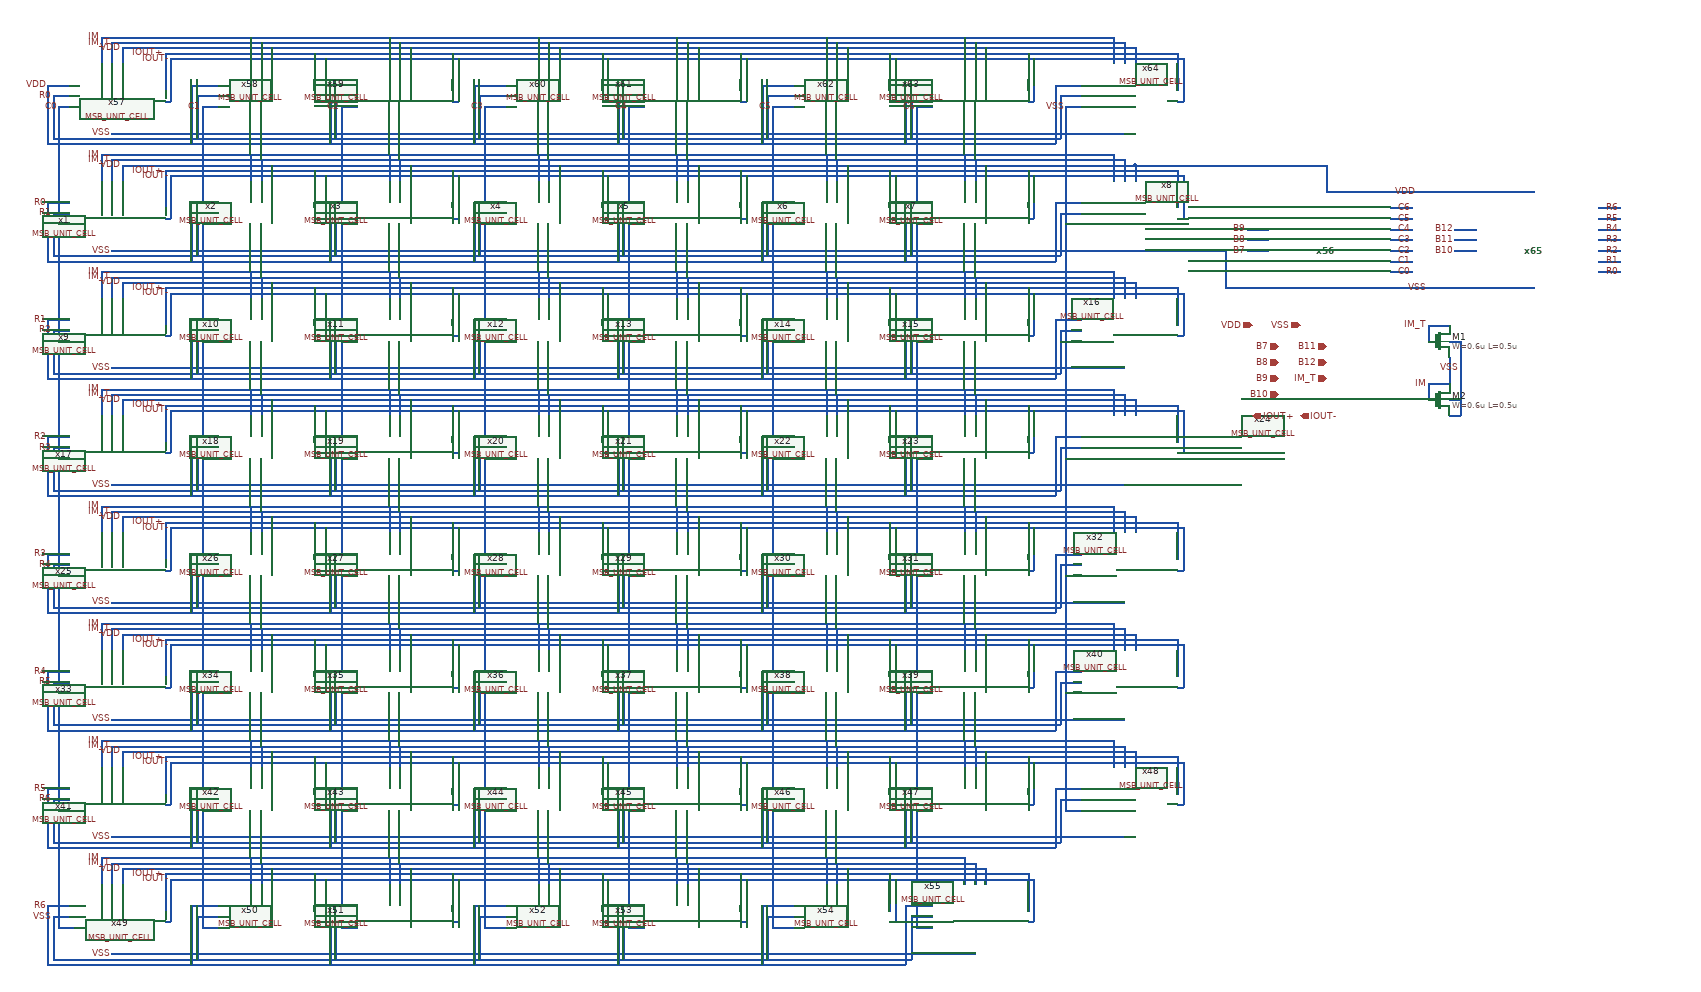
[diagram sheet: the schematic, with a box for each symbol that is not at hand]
v {xschem version=3.1.0 file_version=1.2
}
G {}
K {}
V {}
S {}
E {}
N 210 -1800 210 -1750 {
lab=IM}
N 210 -1800 2110 -1800 {
lab=IM}
N 2110 -1800 2110 -1750 {
lab=IM}
N 2130 -1790 2130 -1750 {
lab=IM_T}
N 2120 -1790 2130 -1790 {
lab=IM_T}
N 230 -1790 2120 -1790 {
lab=IM_T}
N 230 -1790 230 -1750 {
lab=IM_T}
N 250 -1780 250 -1750 {
lab=VDD}
N 250 -1780 2150 -1780 {
lab=VDD}
N 2150 -1780 2150 -1750 {
lab=VDD}
N 2230 -1770 2230 -1700 {
lab=IOUT+}
N 330 -1770 2230 -1770 {
lab=IOUT+}
N 330 -1770 330 -1700 {
lab=IOUT+}
N 330 -1680 340 -1680 {
lab=IOUT-}
N 340 -1760 340 -1680 {
lab=IOUT-}
N 340 -1760 2240 -1760 {
lab=IOUT-}
N 2240 -1760 2240 -1680 {
lab=IOUT-}
N 2230 -1680 2240 -1680 {
lab=IOUT-}
N 230 -1620 2130 -1620 {
lab=VSS}
N 490 -1800 490 -1750 {
lab=IM}
N 510 -1790 510 -1750 {
lab=IM_T}
N 530 -1780 530 -1750 {
lab=VDD}
N 610 -1770 610 -1700 {
lab=IOUT+}
N 610 -1680 630 -1680 {
lab=IOUT-}
N 630 -1760 630 -1680 {
lab=IOUT-}
N 750 -1800 750 -1750 {
lab=IM}
N 770 -1790 770 -1750 {
lab=IM_T}
N 790 -1780 790 -1750 {
lab=VDD}
N 870 -1770 870 -1700 {
lab=IOUT+}
N 880 -1760 880 -1680 {
lab=IOUT-}
N 870 -1680 880 -1680 {
lab=IOUT-}
N 1030 -1800 1030 -1750 {
lab=IM}
N 1050 -1790 1050 -1750 {
lab=IM_T}
N 1070 -1780 1070 -1750 {
lab=VDD}
N 1150 -1770 1150 -1700 {
lab=IOUT+}
N 1150 -1680 1160 -1680 {
lab=IOUT-}
N 1160 -1760 1160 -1680 {
lab=IOUT-}
N 1290 -1800 1290 -1750 {
lab=IM}
N 1310 -1790 1310 -1750 {
lab=IM_T}
N 1330 -1780 1330 -1750 {
lab=VDD}
N 1410 -1770 1410 -1700 {
lab=IOUT+}
N 1420 -1760 1420 -1680 {
lab=IOUT-}
N 1410 -1680 1420 -1680 {
lab=IOUT-}
N 1570 -1800 1570 -1750 {
lab=IM}
N 1590 -1790 1590 -1750 {
lab=IM_T}
N 1610 -1780 1610 -1750 {
lab=VDD}
N 1690 -1770 1690 -1700 {
lab=IOUT+}
N 1700 -1760 1700 -1680 {
lab=IOUT-}
N 1690 -1680 1700 -1680 {
lab=IOUT-}
N 1830 -1800 1830 -1750 {
lab=IM}
N 1850 -1790 1850 -1750 {
lab=IM_T}
N 1870 -1780 1870 -1750 {
lab=VDD}
N 1950 -1770 1950 -1700 {
lab=IOUT+}
N 1950 -1680 1960 -1680 {
lab=IOUT-}
N 1960 -1760 1960 -1680 {
lab=IOUT-}
N 120 -1690 150 -1690 {
lab=R0}
N 120 -1690 120 -1610 {
lab=R0}
N 120 -1610 2010 -1610 {
lab=R0}
N 2010 -1690 2010 -1610 {
lab=R0}
N 2010 -1690 2050 -1690 {
lab=R0}
N 2000 -1710 2050 -1710 {
lab=VDD}
N 2000 -1710 2000 -1600 {
lab=VDD}
N 110 -1600 2000 -1600 {
lab=VDD}
N 110 -1710 110 -1600 {
lab=VDD}
N 110 -1710 150 -1710 {
lab=VDD}
N 380 -1710 430 -1710 {
lab=VDD}
N 380 -1710 380 -1600 {
lab=VDD}
N 390 -1690 390 -1610 {
lab=R0}
N 390 -1690 430 -1690 {
lab=R0}
N 640 -1710 690 -1710 {
lab=VDD}
N 640 -1710 640 -1600 {
lab=VDD}
N 650 -1690 690 -1690 {
lab=R0}
N 650 -1690 650 -1610 {
lab=R0}
N 910 -1710 970 -1710 {
lab=VDD}
N 910 -1710 910 -1600 {
lab=VDD}
N 920 -1690 970 -1690 {
lab=R0}
N 920 -1690 920 -1610 {
lab=R0}
N 1180 -1710 1230 -1710 {
lab=VDD}
N 1180 -1710 1180 -1600 {
lab=VDD}
N 1190 -1690 1230 -1690 {
lab=R0}
N 1190 -1690 1190 -1610 {
lab=R0}
N 1450 -1710 1510 -1710 {
lab=VDD}
N 1450 -1710 1450 -1600 {
lab=VDD}
N 1460 -1690 1510 -1690 {
lab=R0}
N 1460 -1690 1460 -1610 {
lab=R0}
N 1720 -1710 1770 -1710 {
lab=VDD}
N 1720 -1710 1720 -1600 {
lab=VDD}
N 1730 -1690 1770 -1690 {
lab=R0}
N 1730 -1690 1730 -1610 {
lab=R0}
N 210 -1580 210 -1530 {
lab=IM}
N 210 -1580 2110 -1580 {
lab=IM}
N 2110 -1580 2110 -1530 {
lab=IM}
N 2130 -1570 2130 -1530 {
lab=IM_T}
N 2120 -1570 2130 -1570 {
lab=IM_T}
N 230 -1570 2120 -1570 {
lab=IM_T}
N 230 -1570 230 -1530 {
lab=IM_T}
N 250 -1560 250 -1530 {
lab=VDD}
N 250 -1560 2150 -1560 {
lab=VDD}
N 2150 -1560 2150 -1530 {
lab=VDD}
N 2230 -1550 2230 -1480 {
lab=IOUT+}
N 330 -1550 2230 -1550 {
lab=IOUT+}
N 330 -1550 330 -1480 {
lab=IOUT+}
N 330 -1460 340 -1460 {
lab=IOUT-}
N 340 -1540 340 -1460 {
lab=IOUT-}
N 340 -1540 2240 -1540 {
lab=IOUT-}
N 2240 -1540 2240 -1460 {
lab=IOUT-}
N 2230 -1460 2240 -1460 {
lab=IOUT-}
N 230 -1400 2130 -1400 {
lab=VSS}
N 490 -1580 490 -1530 {
lab=IM}
N 510 -1570 510 -1530 {
lab=IM_T}
N 530 -1560 530 -1530 {
lab=VDD}
N 610 -1550 610 -1480 {
lab=IOUT+}
N 610 -1460 630 -1460 {
lab=IOUT-}
N 630 -1540 630 -1460 {
lab=IOUT-}
N 750 -1580 750 -1530 {
lab=IM}
N 770 -1570 770 -1530 {
lab=IM_T}
N 790 -1560 790 -1530 {
lab=VDD}
N 870 -1550 870 -1480 {
lab=IOUT+}
N 880 -1540 880 -1460 {
lab=IOUT-}
N 870 -1460 880 -1460 {
lab=IOUT-}
N 1030 -1580 1030 -1530 {
lab=IM}
N 1050 -1570 1050 -1530 {
lab=IM_T}
N 1070 -1560 1070 -1530 {
lab=VDD}
N 1150 -1550 1150 -1480 {
lab=IOUT+}
N 1150 -1460 1160 -1460 {
lab=IOUT-}
N 1160 -1540 1160 -1460 {
lab=IOUT-}
N 1290 -1580 1290 -1530 {
lab=IM}
N 1310 -1570 1310 -1530 {
lab=IM_T}
N 1330 -1560 1330 -1530 {
lab=VDD}
N 1410 -1550 1410 -1480 {
lab=IOUT+}
N 1420 -1540 1420 -1460 {
lab=IOUT-}
N 1410 -1460 1420 -1460 {
lab=IOUT-}
N 1570 -1580 1570 -1530 {
lab=IM}
N 1590 -1570 1590 -1530 {
lab=IM_T}
N 1610 -1560 1610 -1530 {
lab=VDD}
N 1690 -1550 1690 -1480 {
lab=IOUT+}
N 1700 -1540 1700 -1460 {
lab=IOUT-}
N 1690 -1460 1700 -1460 {
lab=IOUT-}
N 1830 -1580 1830 -1530 {
lab=IM}
N 1850 -1570 1850 -1530 {
lab=IM_T}
N 1870 -1560 1870 -1530 {
lab=VDD}
N 1950 -1550 1950 -1480 {
lab=IOUT+}
N 1950 -1460 1960 -1460 {
lab=IOUT-}
N 1960 -1540 1960 -1460 {
lab=IOUT-}
N 120 -1470 150 -1470 {
lab=R1}
N 120 -1470 120 -1390 {
lab=R1}
N 120 -1390 2010 -1390 {
lab=R1}
N 2010 -1470 2010 -1390 {
lab=R1}
N 2010 -1470 2050 -1470 {
lab=R1}
N 2000 -1490 2050 -1490 {
lab=R0}
N 2000 -1490 2000 -1380 {
lab=R0}
N 110 -1380 2000 -1380 {
lab=R0}
N 110 -1490 110 -1380 {
lab=R0}
N 110 -1490 150 -1490 {
lab=R0}
N 380 -1490 430 -1490 {
lab=R0}
N 380 -1490 380 -1380 {
lab=R0}
N 390 -1470 390 -1390 {
lab=R1}
N 390 -1470 430 -1470 {
lab=R1}
N 640 -1490 690 -1490 {
lab=R0}
N 640 -1490 640 -1380 {
lab=R0}
N 650 -1470 690 -1470 {
lab=R1}
N 650 -1470 650 -1390 {
lab=R1}
N 910 -1490 970 -1490 {
lab=R0}
N 910 -1490 910 -1380 {
lab=R0}
N 920 -1470 970 -1470 {
lab=R1}
N 920 -1470 920 -1390 {
lab=R1}
N 1180 -1490 1230 -1490 {
lab=R0}
N 1180 -1490 1180 -1380 {
lab=R0}
N 1190 -1470 1230 -1470 {
lab=R1}
N 1190 -1470 1190 -1390 {
lab=R1}
N 1450 -1490 1510 -1490 {
lab=R0}
N 1450 -1490 1450 -1380 {
lab=R0}
N 1460 -1470 1510 -1470 {
lab=R1}
N 1460 -1470 1460 -1390 {
lab=R1}
N 1720 -1490 1770 -1490 {
lab=R0}
N 1720 -1490 1720 -1380 {
lab=R0}
N 1730 -1470 1770 -1470 {
lab=R1}
N 1730 -1470 1730 -1390 {
lab=R1}
N 210 -1360 210 -1310 {
lab=IM}
N 210 -1360 2110 -1360 {
lab=IM}
N 2110 -1360 2110 -1310 {
lab=IM}
N 2130 -1350 2130 -1310 {
lab=IM_T}
N 2120 -1350 2130 -1350 {
lab=IM_T}
N 230 -1350 2120 -1350 {
lab=IM_T}
N 230 -1350 230 -1310 {
lab=IM_T}
N 250 -1340 250 -1310 {
lab=VDD}
N 250 -1340 2150 -1340 {
lab=VDD}
N 2150 -1340 2150 -1310 {
lab=VDD}
N 2230 -1330 2230 -1260 {
lab=IOUT+}
N 330 -1330 2230 -1330 {
lab=IOUT+}
N 330 -1330 330 -1260 {
lab=IOUT+}
N 330 -1240 340 -1240 {
lab=IOUT-}
N 340 -1320 340 -1240 {
lab=IOUT-}
N 340 -1320 2240 -1320 {
lab=IOUT-}
N 2240 -1320 2240 -1240 {
lab=IOUT-}
N 2230 -1240 2240 -1240 {
lab=IOUT-}
N 230 -1180 2130 -1180 {
lab=VSS}
N 490 -1360 490 -1310 {
lab=IM}
N 510 -1350 510 -1310 {
lab=IM_T}
N 530 -1340 530 -1310 {
lab=VDD}
N 610 -1330 610 -1260 {
lab=IOUT+}
N 610 -1240 630 -1240 {
lab=IOUT-}
N 630 -1320 630 -1240 {
lab=IOUT-}
N 750 -1360 750 -1310 {
lab=IM}
N 770 -1350 770 -1310 {
lab=IM_T}
N 790 -1340 790 -1310 {
lab=VDD}
N 870 -1330 870 -1260 {
lab=IOUT+}
N 880 -1320 880 -1240 {
lab=IOUT-}
N 870 -1240 880 -1240 {
lab=IOUT-}
N 1030 -1360 1030 -1310 {
lab=IM}
N 1050 -1350 1050 -1310 {
lab=IM_T}
N 1070 -1340 1070 -1310 {
lab=VDD}
N 1150 -1330 1150 -1260 {
lab=IOUT+}
N 1150 -1240 1160 -1240 {
lab=IOUT-}
N 1160 -1320 1160 -1240 {
lab=IOUT-}
N 1290 -1360 1290 -1310 {
lab=IM}
N 1310 -1350 1310 -1310 {
lab=IM_T}
N 1330 -1340 1330 -1310 {
lab=VDD}
N 1410 -1330 1410 -1260 {
lab=IOUT+}
N 1420 -1320 1420 -1240 {
lab=IOUT-}
N 1410 -1240 1420 -1240 {
lab=IOUT-}
N 1570 -1360 1570 -1310 {
lab=IM}
N 1590 -1350 1590 -1310 {
lab=IM_T}
N 1610 -1340 1610 -1310 {
lab=VDD}
N 1690 -1330 1690 -1260 {
lab=IOUT+}
N 1700 -1320 1700 -1240 {
lab=IOUT-}
N 1690 -1240 1700 -1240 {
lab=IOUT-}
N 1830 -1360 1830 -1310 {
lab=IM}
N 1850 -1350 1850 -1310 {
lab=IM_T}
N 1870 -1340 1870 -1310 {
lab=VDD}
N 1950 -1330 1950 -1260 {
lab=IOUT+}
N 1950 -1240 1960 -1240 {
lab=IOUT-}
N 1960 -1320 1960 -1240 {
lab=IOUT-}
N 120 -1250 150 -1250 {
lab=R2}
N 120 -1250 120 -1170 {
lab=R2}
N 120 -1170 2010 -1170 {
lab=R2}
N 2010 -1250 2010 -1170 {
lab=R2}
N 2010 -1250 2050 -1250 {
lab=R2}
N 2000 -1270 2050 -1270 {
lab=R1}
N 2000 -1270 2000 -1160 {
lab=R1}
N 110 -1160 2000 -1160 {
lab=R1}
N 110 -1270 110 -1160 {
lab=R1}
N 110 -1270 150 -1270 {
lab=R1}
N 380 -1270 430 -1270 {
lab=R1}
N 380 -1270 380 -1160 {
lab=R1}
N 390 -1250 390 -1170 {
lab=R2}
N 390 -1250 430 -1250 {
lab=R2}
N 640 -1270 690 -1270 {
lab=R1}
N 640 -1270 640 -1160 {
lab=R1}
N 650 -1250 690 -1250 {
lab=R2}
N 650 -1250 650 -1170 {
lab=R2}
N 910 -1270 970 -1270 {
lab=R1}
N 910 -1270 910 -1160 {
lab=R1}
N 920 -1250 970 -1250 {
lab=R2}
N 920 -1250 920 -1170 {
lab=R2}
N 1180 -1270 1230 -1270 {
lab=R1}
N 1180 -1270 1180 -1160 {
lab=R1}
N 1190 -1250 1230 -1250 {
lab=R2}
N 1190 -1250 1190 -1170 {
lab=R2}
N 1450 -1270 1510 -1270 {
lab=R1}
N 1450 -1270 1450 -1160 {
lab=R1}
N 1460 -1250 1510 -1250 {
lab=R2}
N 1460 -1250 1460 -1170 {
lab=R2}
N 1720 -1270 1770 -1270 {
lab=R1}
N 1720 -1270 1720 -1160 {
lab=R1}
N 1730 -1250 1770 -1250 {
lab=R2}
N 1730 -1250 1730 -1170 {
lab=R2}
N 210 -1140 210 -1090 {
lab=IM}
N 210 -1140 2110 -1140 {
lab=IM}
N 2110 -1140 2110 -1090 {
lab=IM}
N 2130 -1130 2130 -1090 {
lab=IM_T}
N 2120 -1130 2130 -1130 {
lab=IM_T}
N 230 -1130 2120 -1130 {
lab=IM_T}
N 230 -1130 230 -1090 {
lab=IM_T}
N 250 -1120 250 -1090 {
lab=VDD}
N 250 -1120 2150 -1120 {
lab=VDD}
N 2150 -1120 2150 -1090 {
lab=VDD}
N 2230 -1110 2230 -1040 {
lab=IOUT+}
N 330 -1110 2230 -1110 {
lab=IOUT+}
N 330 -1110 330 -1040 {
lab=IOUT+}
N 330 -1020 340 -1020 {
lab=IOUT-}
N 340 -1100 340 -1020 {
lab=IOUT-}
N 340 -1100 2240 -1100 {
lab=IOUT-}
N 2240 -1100 2240 -1020 {
lab=IOUT-}
N 2230 -1020 2240 -1020 {
lab=IOUT-}
N 230 -960 2130 -960 {
lab=VSS}
N 490 -1140 490 -1090 {
lab=IM}
N 510 -1130 510 -1090 {
lab=IM_T}
N 530 -1120 530 -1090 {
lab=VDD}
N 610 -1110 610 -1040 {
lab=IOUT+}
N 610 -1020 630 -1020 {
lab=IOUT-}
N 630 -1100 630 -1020 {
lab=IOUT-}
N 750 -1140 750 -1090 {
lab=IM}
N 770 -1130 770 -1090 {
lab=IM_T}
N 790 -1120 790 -1090 {
lab=VDD}
N 870 -1110 870 -1040 {
lab=IOUT+}
N 880 -1100 880 -1020 {
lab=IOUT-}
N 870 -1020 880 -1020 {
lab=IOUT-}
N 1030 -1140 1030 -1090 {
lab=IM}
N 1050 -1130 1050 -1090 {
lab=IM_T}
N 1070 -1120 1070 -1090 {
lab=VDD}
N 1150 -1110 1150 -1040 {
lab=IOUT+}
N 1150 -1020 1160 -1020 {
lab=IOUT-}
N 1160 -1100 1160 -1020 {
lab=IOUT-}
N 1290 -1140 1290 -1090 {
lab=IM}
N 1310 -1130 1310 -1090 {
lab=IM_T}
N 1330 -1120 1330 -1090 {
lab=VDD}
N 1410 -1110 1410 -1040 {
lab=IOUT+}
N 1420 -1100 1420 -1020 {
lab=IOUT-}
N 1410 -1020 1420 -1020 {
lab=IOUT-}
N 1570 -1140 1570 -1090 {
lab=IM}
N 1590 -1130 1590 -1090 {
lab=IM_T}
N 1610 -1120 1610 -1090 {
lab=VDD}
N 1690 -1110 1690 -1040 {
lab=IOUT+}
N 1700 -1100 1700 -1020 {
lab=IOUT-}
N 1690 -1020 1700 -1020 {
lab=IOUT-}
N 1830 -1140 1830 -1090 {
lab=IM}
N 1850 -1130 1850 -1090 {
lab=IM_T}
N 1870 -1120 1870 -1090 {
lab=VDD}
N 1950 -1110 1950 -1040 {
lab=IOUT+}
N 1950 -1020 1960 -1020 {
lab=IOUT-}
N 1960 -1100 1960 -1020 {
lab=IOUT-}
N 120 -1030 150 -1030 {
lab=R3}
N 120 -1030 120 -950 {
lab=R3}
N 120 -950 2010 -950 {
lab=R3}
N 2010 -1030 2010 -950 {
lab=R3}
N 2010 -1030 2050 -1030 {
lab=R3}
N 2000 -1050 2050 -1050 {
lab=R2}
N 2000 -1050 2000 -940 {
lab=R2}
N 110 -940 2000 -940 {
lab=R2}
N 110 -1050 110 -940 {
lab=R2}
N 110 -1050 150 -1050 {
lab=R2}
N 380 -1050 430 -1050 {
lab=R2}
N 380 -1050 380 -940 {
lab=R2}
N 390 -1030 390 -950 {
lab=R3}
N 390 -1030 430 -1030 {
lab=R3}
N 640 -1050 690 -1050 {
lab=R2}
N 640 -1050 640 -940 {
lab=R2}
N 650 -1030 690 -1030 {
lab=R3}
N 650 -1030 650 -950 {
lab=R3}
N 910 -1050 970 -1050 {
lab=R2}
N 910 -1050 910 -940 {
lab=R2}
N 920 -1030 970 -1030 {
lab=R3}
N 920 -1030 920 -950 {
lab=R3}
N 1180 -1050 1230 -1050 {
lab=R2}
N 1180 -1050 1180 -940 {
lab=R2}
N 1190 -1030 1230 -1030 {
lab=R3}
N 1190 -1030 1190 -950 {
lab=R3}
N 1450 -1050 1510 -1050 {
lab=R2}
N 1450 -1050 1450 -940 {
lab=R2}
N 1460 -1030 1510 -1030 {
lab=R3}
N 1460 -1030 1460 -950 {
lab=R3}
N 1720 -1050 1770 -1050 {
lab=R2}
N 1720 -1050 1720 -940 {
lab=R2}
N 1730 -1030 1770 -1030 {
lab=R3}
N 1730 -1030 1730 -950 {
lab=R3}
N 210 -920 210 -870 {
lab=IM}
N 210 -920 2110 -920 {
lab=IM}
N 2110 -920 2110 -870 {
lab=IM}
N 2130 -910 2130 -870 {
lab=IM_T}
N 2120 -910 2130 -910 {
lab=IM_T}
N 230 -910 2120 -910 {
lab=IM_T}
N 230 -910 230 -870 {
lab=IM_T}
N 250 -900 250 -870 {
lab=VDD}
N 250 -900 2150 -900 {
lab=VDD}
N 2150 -900 2150 -870 {
lab=VDD}
N 2230 -890 2230 -820 {
lab=IOUT+}
N 330 -890 2230 -890 {
lab=IOUT+}
N 330 -890 330 -820 {
lab=IOUT+}
N 330 -800 340 -800 {
lab=IOUT-}
N 340 -880 340 -800 {
lab=IOUT-}
N 340 -880 2240 -880 {
lab=IOUT-}
N 2240 -880 2240 -800 {
lab=IOUT-}
N 2230 -800 2240 -800 {
lab=IOUT-}
N 230 -740 2130 -740 {
lab=VSS}
N 490 -920 490 -870 {
lab=IM}
N 510 -910 510 -870 {
lab=IM_T}
N 530 -900 530 -870 {
lab=VDD}
N 610 -890 610 -820 {
lab=IOUT+}
N 610 -800 630 -800 {
lab=IOUT-}
N 630 -880 630 -800 {
lab=IOUT-}
N 750 -920 750 -870 {
lab=IM}
N 770 -910 770 -870 {
lab=IM_T}
N 790 -900 790 -870 {
lab=VDD}
N 870 -890 870 -820 {
lab=IOUT+}
N 880 -880 880 -800 {
lab=IOUT-}
N 870 -800 880 -800 {
lab=IOUT-}
N 1030 -920 1030 -870 {
lab=IM}
N 1050 -910 1050 -870 {
lab=IM_T}
N 1070 -900 1070 -870 {
lab=VDD}
N 1150 -890 1150 -820 {
lab=IOUT+}
N 1150 -800 1160 -800 {
lab=IOUT-}
N 1160 -880 1160 -800 {
lab=IOUT-}
N 1290 -920 1290 -870 {
lab=IM}
N 1310 -910 1310 -870 {
lab=IM_T}
N 1330 -900 1330 -870 {
lab=VDD}
N 1410 -890 1410 -820 {
lab=IOUT+}
N 1420 -880 1420 -800 {
lab=IOUT-}
N 1410 -800 1420 -800 {
lab=IOUT-}
N 1570 -920 1570 -870 {
lab=IM}
N 1590 -910 1590 -870 {
lab=IM_T}
N 1610 -900 1610 -870 {
lab=VDD}
N 1690 -890 1690 -820 {
lab=IOUT+}
N 1700 -880 1700 -800 {
lab=IOUT-}
N 1690 -800 1700 -800 {
lab=IOUT-}
N 1830 -920 1830 -870 {
lab=IM}
N 1850 -910 1850 -870 {
lab=IM_T}
N 1870 -900 1870 -870 {
lab=VDD}
N 1950 -890 1950 -820 {
lab=IOUT+}
N 1950 -800 1960 -800 {
lab=IOUT-}
N 1960 -880 1960 -800 {
lab=IOUT-}
N 120 -810 150 -810 {
lab=R4}
N 120 -810 120 -730 {
lab=R4}
N 120 -730 2010 -730 {
lab=R4}
N 2010 -810 2010 -730 {
lab=R4}
N 2010 -810 2050 -810 {
lab=R4}
N 2000 -830 2050 -830 {
lab=R3}
N 2000 -830 2000 -720 {
lab=R3}
N 110 -720 2000 -720 {
lab=R3}
N 110 -830 110 -720 {
lab=R3}
N 110 -830 150 -830 {
lab=R3}
N 380 -830 430 -830 {
lab=R3}
N 380 -830 380 -720 {
lab=R3}
N 390 -810 390 -730 {
lab=R4}
N 390 -810 430 -810 {
lab=R4}
N 640 -830 690 -830 {
lab=R3}
N 640 -830 640 -720 {
lab=R3}
N 650 -810 690 -810 {
lab=R4}
N 650 -810 650 -730 {
lab=R4}
N 910 -830 970 -830 {
lab=R3}
N 910 -830 910 -720 {
lab=R3}
N 920 -810 970 -810 {
lab=R4}
N 920 -810 920 -730 {
lab=R4}
N 1180 -830 1230 -830 {
lab=R3}
N 1180 -830 1180 -720 {
lab=R3}
N 1190 -810 1230 -810 {
lab=R4}
N 1190 -810 1190 -730 {
lab=R4}
N 1450 -830 1510 -830 {
lab=R3}
N 1450 -830 1450 -720 {
lab=R3}
N 1460 -810 1510 -810 {
lab=R4}
N 1460 -810 1460 -730 {
lab=R4}
N 1720 -830 1770 -830 {
lab=R3}
N 1720 -830 1720 -720 {
lab=R3}
N 1730 -810 1770 -810 {
lab=R4}
N 1730 -810 1730 -730 {
lab=R4}
N 210 -700 210 -650 {
lab=IM}
N 210 -700 2110 -700 {
lab=IM}
N 2110 -700 2110 -650 {
lab=IM}
N 2130 -690 2130 -650 {
lab=IM_T}
N 2120 -690 2130 -690 {
lab=IM_T}
N 230 -690 2120 -690 {
lab=IM_T}
N 230 -690 230 -650 {
lab=IM_T}
N 250 -680 250 -650 {
lab=VDD}
N 250 -680 2150 -680 {
lab=VDD}
N 2150 -680 2150 -650 {
lab=VDD}
N 2230 -670 2230 -600 {
lab=IOUT+}
N 330 -670 2230 -670 {
lab=IOUT+}
N 330 -670 330 -600 {
lab=IOUT+}
N 330 -580 340 -580 {
lab=IOUT-}
N 340 -660 340 -580 {
lab=IOUT-}
N 340 -660 2240 -660 {
lab=IOUT-}
N 2240 -660 2240 -580 {
lab=IOUT-}
N 2230 -580 2240 -580 {
lab=IOUT-}
N 230 -520 2130 -520 {
lab=VSS}
N 490 -700 490 -650 {
lab=IM}
N 510 -690 510 -650 {
lab=IM_T}
N 530 -680 530 -650 {
lab=VDD}
N 610 -670 610 -600 {
lab=IOUT+}
N 610 -580 630 -580 {
lab=IOUT-}
N 630 -660 630 -580 {
lab=IOUT-}
N 750 -700 750 -650 {
lab=IM}
N 770 -690 770 -650 {
lab=IM_T}
N 790 -680 790 -650 {
lab=VDD}
N 870 -670 870 -600 {
lab=IOUT+}
N 880 -660 880 -580 {
lab=IOUT-}
N 870 -580 880 -580 {
lab=IOUT-}
N 1030 -700 1030 -650 {
lab=IM}
N 1050 -690 1050 -650 {
lab=IM_T}
N 1070 -680 1070 -650 {
lab=VDD}
N 1150 -670 1150 -600 {
lab=IOUT+}
N 1150 -580 1160 -580 {
lab=IOUT-}
N 1160 -660 1160 -580 {
lab=IOUT-}
N 1290 -700 1290 -650 {
lab=IM}
N 1310 -690 1310 -650 {
lab=IM_T}
N 1330 -680 1330 -650 {
lab=VDD}
N 1410 -670 1410 -600 {
lab=IOUT+}
N 1420 -660 1420 -580 {
lab=IOUT-}
N 1410 -580 1420 -580 {
lab=IOUT-}
N 1570 -700 1570 -650 {
lab=IM}
N 1590 -690 1590 -650 {
lab=IM_T}
N 1610 -680 1610 -650 {
lab=VDD}
N 1690 -670 1690 -600 {
lab=IOUT+}
N 1700 -660 1700 -580 {
lab=IOUT-}
N 1690 -580 1700 -580 {
lab=IOUT-}
N 1830 -700 1830 -650 {
lab=IM}
N 1850 -690 1850 -650 {
lab=IM_T}
N 1870 -680 1870 -650 {
lab=VDD}
N 1950 -670 1950 -600 {
lab=IOUT+}
N 1950 -580 1960 -580 {
lab=IOUT-}
N 1960 -660 1960 -580 {
lab=IOUT-}
N 120 -590 150 -590 {
lab=R5}
N 120 -590 120 -510 {
lab=R5}
N 120 -510 2010 -510 {
lab=R5}
N 2010 -590 2010 -510 {
lab=R5}
N 2010 -590 2050 -590 {
lab=R5}
N 2000 -610 2050 -610 {
lab=R4}
N 2000 -610 2000 -500 {
lab=R4}
N 110 -500 2000 -500 {
lab=R4}
N 110 -610 110 -500 {
lab=R4}
N 110 -610 150 -610 {
lab=R4}
N 380 -610 430 -610 {
lab=R4}
N 380 -610 380 -500 {
lab=R4}
N 390 -590 390 -510 {
lab=R5}
N 390 -590 430 -590 {
lab=R5}
N 640 -610 690 -610 {
lab=R4}
N 640 -610 640 -500 {
lab=R4}
N 650 -590 690 -590 {
lab=R5}
N 650 -590 650 -510 {
lab=R5}
N 910 -610 970 -610 {
lab=R4}
N 910 -610 910 -500 {
lab=R4}
N 920 -590 970 -590 {
lab=R5}
N 920 -590 920 -510 {
lab=R5}
N 1180 -610 1230 -610 {
lab=R4}
N 1180 -610 1180 -500 {
lab=R4}
N 1190 -590 1230 -590 {
lab=R5}
N 1190 -590 1190 -510 {
lab=R5}
N 1450 -610 1510 -610 {
lab=R4}
N 1450 -610 1450 -500 {
lab=R4}
N 1460 -590 1510 -590 {
lab=R5}
N 1460 -590 1460 -510 {
lab=R5}
N 1720 -610 1770 -610 {
lab=R4}
N 1720 -610 1720 -500 {
lab=R4}
N 1730 -590 1770 -590 {
lab=R5}
N 1730 -590 1730 -510 {
lab=R5}
N 210 -480 210 -430 {
lab=IM}
N 210 -480 2110 -480 {
lab=IM}
N 2110 -480 2110 -430 {
lab=IM}
N 2130 -470 2130 -430 {
lab=IM_T}
N 2120 -470 2130 -470 {
lab=IM_T}
N 230 -470 2120 -470 {
lab=IM_T}
N 230 -470 230 -430 {
lab=IM_T}
N 250 -460 250 -430 {
lab=VDD}
N 250 -460 2150 -460 {
lab=VDD}
N 2150 -460 2150 -430 {
lab=VDD}
N 2230 -450 2230 -380 {
lab=IOUT+}
N 330 -450 2230 -450 {
lab=IOUT+}
N 330 -450 330 -380 {
lab=IOUT+}
N 330 -360 340 -360 {
lab=IOUT-}
N 340 -440 340 -360 {
lab=IOUT-}
N 340 -440 2240 -440 {
lab=IOUT-}
N 2240 -440 2240 -360 {
lab=IOUT-}
N 2230 -360 2240 -360 {
lab=IOUT-}
N 230 -300 2130 -300 {
lab=VSS}
N 490 -480 490 -430 {
lab=IM}
N 510 -470 510 -430 {
lab=IM_T}
N 530 -460 530 -430 {
lab=VDD}
N 610 -450 610 -380 {
lab=IOUT+}
N 610 -360 630 -360 {
lab=IOUT-}
N 630 -440 630 -360 {
lab=IOUT-}
N 750 -480 750 -430 {
lab=IM}
N 770 -470 770 -430 {
lab=IM_T}
N 790 -460 790 -430 {
lab=VDD}
N 870 -450 870 -380 {
lab=IOUT+}
N 880 -440 880 -360 {
lab=IOUT-}
N 870 -360 880 -360 {
lab=IOUT-}
N 1030 -480 1030 -430 {
lab=IM}
N 1050 -470 1050 -430 {
lab=IM_T}
N 1070 -460 1070 -430 {
lab=VDD}
N 1150 -450 1150 -380 {
lab=IOUT+}
N 1150 -360 1160 -360 {
lab=IOUT-}
N 1160 -440 1160 -360 {
lab=IOUT-}
N 1290 -480 1290 -430 {
lab=IM}
N 1310 -470 1310 -430 {
lab=IM_T}
N 1330 -460 1330 -430 {
lab=VDD}
N 1410 -450 1410 -380 {
lab=IOUT+}
N 1420 -440 1420 -360 {
lab=IOUT-}
N 1410 -360 1420 -360 {
lab=IOUT-}
N 1570 -480 1570 -430 {
lab=IM}
N 1590 -470 1590 -430 {
lab=IM_T}
N 1610 -460 1610 -430 {
lab=VDD}
N 1690 -450 1690 -380 {
lab=IOUT+}
N 1700 -440 1700 -360 {
lab=IOUT-}
N 1690 -360 1700 -360 {
lab=IOUT-}
N 1830 -480 1830 -430 {
lab=IM}
N 1850 -470 1850 -430 {
lab=IM_T}
N 1870 -460 1870 -430 {
lab=VDD}
N 1950 -450 1950 -380 {
lab=IOUT+}
N 1950 -360 1960 -360 {
lab=IOUT-}
N 1960 -440 1960 -360 {
lab=IOUT-}
N 120 -370 150 -370 {
lab=R6}
N 120 -370 120 -290 {
lab=R6}
N 120 -290 2010 -290 {
lab=R6}
N 2010 -370 2010 -290 {
lab=R6}
N 2010 -370 2050 -370 {
lab=R6}
N 2000 -390 2050 -390 {
lab=R5}
N 2000 -390 2000 -280 {
lab=R5}
N 110 -280 2000 -280 {
lab=R5}
N 110 -390 110 -280 {
lab=R5}
N 110 -390 150 -390 {
lab=R5}
N 380 -390 430 -390 {
lab=R5}
N 380 -390 380 -280 {
lab=R5}
N 390 -370 390 -290 {
lab=R6}
N 390 -370 430 -370 {
lab=R6}
N 640 -390 690 -390 {
lab=R5}
N 640 -390 640 -280 {
lab=R5}
N 650 -370 690 -370 {
lab=R6}
N 650 -370 650 -290 {
lab=R6}
N 910 -390 970 -390 {
lab=R5}
N 910 -390 910 -280 {
lab=R5}
N 920 -370 970 -370 {
lab=R6}
N 920 -370 920 -290 {
lab=R6}
N 1180 -390 1230 -390 {
lab=R5}
N 1180 -390 1180 -280 {
lab=R5}
N 1190 -370 1230 -370 {
lab=R6}
N 1190 -370 1190 -290 {
lab=R6}
N 1450 -390 1510 -390 {
lab=R5}
N 1450 -390 1450 -280 {
lab=R5}
N 1460 -370 1510 -370 {
lab=R6}
N 1460 -370 1460 -290 {
lab=R6}
N 1720 -390 1770 -390 {
lab=R5}
N 1720 -390 1720 -280 {
lab=R5}
N 1730 -370 1770 -370 {
lab=R6}
N 1730 -370 1730 -290 {
lab=R6}
N 210 -260 210 -210 {
lab=IM}
N 230 -250 230 -210 {
lab=IM_T}
N 250 -240 250 -210 {
lab=VDD}
N 330 -230 330 -160 {
lab=IOUT+}
N 330 -140 340 -140 {
lab=IOUT-}
N 340 -220 340 -140 {
lab=IOUT-}
N 490 -260 490 -210 {
lab=IM}
N 510 -250 510 -210 {
lab=IM_T}
N 530 -240 530 -210 {
lab=VDD}
N 610 -230 610 -160 {
lab=IOUT+}
N 610 -140 630 -140 {
lab=IOUT-}
N 630 -220 630 -140 {
lab=IOUT-}
N 750 -260 750 -210 {
lab=IM}
N 770 -250 770 -210 {
lab=IM_T}
N 790 -240 790 -210 {
lab=VDD}
N 870 -230 870 -160 {
lab=IOUT+}
N 880 -220 880 -140 {
lab=IOUT-}
N 870 -140 880 -140 {
lab=IOUT-}
N 1030 -260 1030 -210 {
lab=IM}
N 1050 -250 1050 -210 {
lab=IM_T}
N 1070 -240 1070 -210 {
lab=VDD}
N 1150 -230 1150 -160 {
lab=IOUT+}
N 1150 -140 1160 -140 {
lab=IOUT-}
N 1160 -220 1160 -140 {
lab=IOUT-}
N 1290 -260 1290 -210 {
lab=IM}
N 1310 -250 1310 -210 {
lab=IM_T}
N 1330 -240 1330 -210 {
lab=VDD}
N 1410 -230 1410 -160 {
lab=IOUT+}
N 1420 -220 1420 -140 {
lab=IOUT-}
N 1410 -140 1420 -140 {
lab=IOUT-}
N 1570 -260 1570 -210 {
lab=IM}
N 1590 -250 1590 -210 {
lab=IM_T}
N 1610 -240 1610 -210 {
lab=VDD}
N 1690 -230 1690 -160 {
lab=IOUT+}
N 1700 -220 1700 -140 {
lab=IOUT-}
N 1690 -140 1700 -140 {
lab=IOUT-}
N 1830 -260 1830 -210 {
lab=IM}
N 1850 -250 1850 -210 {
lab=IM_T}
N 1870 -240 1870 -210 {
lab=VDD}
N 1950 -230 1950 -160 {
lab=IOUT+}
N 1950 -140 1960 -140 {
lab=IOUT-}
N 1960 -220 1960 -140 {
lab=IOUT-}
N 120 -150 150 -150 {
lab=VSS}
N 120 -150 120 -70 {
lab=VSS}
N 110 -170 110 -60 {
lab=R6}
N 110 -170 150 -170 {
lab=R6}
N 380 -170 430 -170 {
lab=R6}
N 380 -170 380 -60 {
lab=R6}
N 390 -150 390 -70 {
lab=VSS}
N 390 -150 430 -150 {
lab=VSS}
N 640 -170 690 -170 {
lab=R6}
N 640 -170 640 -60 {
lab=R6}
N 650 -150 690 -150 {
lab=VSS}
N 650 -150 650 -70 {
lab=VSS}
N 910 -170 970 -170 {
lab=R6}
N 910 -170 910 -60 {
lab=R6}
N 920 -150 970 -150 {
lab=VSS}
N 920 -150 920 -70 {
lab=VSS}
N 1180 -170 1230 -170 {
lab=R6}
N 1180 -170 1180 -60 {
lab=R6}
N 1190 -150 1230 -150 {
lab=VSS}
N 1190 -150 1190 -70 {
lab=VSS}
N 1450 -170 1510 -170 {
lab=R6}
N 1450 -170 1450 -60 {
lab=R6}
N 1460 -150 1510 -150 {
lab=VSS}
N 1460 -150 1460 -70 {
lab=VSS}
N 1720 -170 1770 -170 {
lab=R6}
N 1720 -170 1720 -60 {
lab=R6}
N 1730 -150 1770 -150 {
lab=VSS}
N 1730 -150 1730 -70 {
lab=VSS}
N 130 -1670 150 -1670 {
lab=C0}
N 130 -1670 130 -130 {
lab=C0}
N 130 -130 160 -130 {
lab=C0}
N 130 -350 150 -350 {
lab=C0}
N 130 -570 150 -570 {
lab=C0}
N 130 -790 150 -790 {
lab=C0}
N 130 -1010 150 -1010 {
lab=C0}
N 130 -1230 150 -1230 {
lab=C0}
N 130 -1450 150 -1450 {
lab=C0}
N 400 -1670 430 -1670 {
lab=C1}
N 400 -1670 400 -130 {
lab=C1}
N 400 -130 430 -130 {
lab=C1}
N 660 -130 690 -130 {
lab=C2}
N 660 -1670 660 -130 {
lab=C2}
N 660 -1670 690 -1670 {
lab=C2}
N 930 -1670 970 -1670 {
lab=C3}
N 930 -1670 930 -130 {
lab=C3}
N 930 -130 970 -130 {
lab=C3}
N 1200 -130 1230 -130 {
lab=C4}
N 1200 -1670 1200 -130 {
lab=C4}
N 1200 -1670 1230 -1670 {
lab=C4}
N 1470 -1670 1510 -1670 {
lab=C5}
N 1470 -1670 1470 -130 {
lab=C5}
N 1470 -130 1510 -130 {
lab=C5}
N 1740 -130 1770 -130 {
lab=C6}
N 1740 -1670 1740 -130 {
lab=C6}
N 1740 -1670 1770 -1670 {
lab=C6}
N 2020 -1670 2050 -1670 {
lab=VSS}
N 2020 -350 2050 -350 {
lab=VSS}
N 2020 -570 2050 -570 {
lab=VSS}
N 1740 -570 1770 -570 {
lab=C6}
N 1740 -350 1770 -350 {
lab=C6}
N 1470 -350 1510 -350 {
lab=C5}
N 2020 -1450 2050 -1450 {
lab=VSS}
N 1740 -1450 1770 -1450 {
lab=C6}
N 1470 -1450 1510 -1450 {
lab=C5}
N 1200 -1450 1230 -1450 {
lab=C4}
N 930 -1450 970 -1450 {
lab=C3}
N 660 -1450 690 -1450 {
lab=C2}
N 400 -1450 430 -1450 {
lab=C1}
N 400 -1230 430 -1230 {
lab=C1}
N 660 -1230 690 -1230 {
lab=C2}
N 930 -1230 970 -1230 {
lab=C3}
N 1470 -1230 1510 -1230 {
lab=C5}
N 1200 -1230 1230 -1230 {
lab=C4}
N 1740 -1230 1770 -1230 {
lab=C6}
N 2010 -1230 2050 -1230 {
lab=R2}
N 2020 -1010 2050 -1010 {
lab=VSS}
N 1740 -1010 1770 -1010 {
lab=C6}
N 1470 -1010 1510 -1010 {
lab=C5}
N 1200 -1010 1230 -1010 {
lab=C4}
N 930 -1010 970 -1010 {
lab=C3}
N 660 -1010 690 -1010 {
lab=C2}
N 400 -1010 430 -1010 {
lab=C1}
N 400 -790 430 -790 {
lab=C1}
N 660 -790 690 -790 {
lab=C2}
N 930 -790 970 -790 {
lab=C3}
N 1200 -790 1230 -790 {
lab=C4}
N 1470 -790 1510 -790 {
lab=C5}
N 1740 -790 1770 -790 {
lab=C6}
N 2020 -790 2050 -790 {
lab=VSS}
N 1470 -570 1510 -570 {
lab=C5}
N 1200 -570 1230 -570 {
lab=C4}
N 930 -570 970 -570 {
lab=C3}
N 660 -570 690 -570 {
lab=C2}
N 400 -570 430 -570 {
lab=C1}
N 400 -350 430 -350 {
lab=C1}
N 680 -350 690 -350 {
lab=C2}
N 660 -350 680 -350 {
lab=C2}
N 930 -350 970 -350 {
lab=C3}
N 1200 -350 1230 -350 {
lab=C4}
N 230 -80 1850 -80 {
lab=VSS}
N 120 -70 1730 -70 {
lab=VSS}
N 110 -60 1720 -60 {
lab=R6}
N 210 -260 1830 -260 {
lab=IM}
N 230 -250 1850 -250 {
lab=IM_T}
N 250 -240 1870 -240 {
lab=VDD}
N 330 -230 1950 -230 {
lab=IOUT+}
N 340 -220 1960 -220 {
lab=IOUT-}
N 2020 -1670 2020 -350 {
lab=VSS}
N 2150 -1560 2510 -1560 {
lab=VDD}
N 2510 -1560 2510 -1510 {
lab=VDD}
N 2510 -1510 2900 -1510 {
lab=VDD}
N 2510 -1330 2900 -1330 {
lab=VSS}
N 2320 -1330 2510 -1330 {
lab=VSS}
N 2320 -1400 2320 -1330 {
lab=VSS}
N 2130 -1400 2320 -1400 {
lab=VSS}
N 2360 -1440 2400 -1440 {
lab=B9}
N 2360 -1420 2400 -1420 {
lab=B8}
N 2360 -1400 2400 -1400 {
lab=B7}
N 2750 -1440 2790 -1440 {
lab=B12}
N 2750 -1420 2790 -1420 {
lab=B11}
N 2750 -1400 2790 -1400 {
lab=B10}
N 2630 -1480 2670 -1480 {
lab=C6}
N 2630 -1460 2670 -1460 {
lab=C5}
N 2630 -1440 2640 -1440 {
lab=C4}
N 2640 -1440 2670 -1440 {
lab=C4}
N 2630 -1420 2670 -1420 {
lab=C3}
N 2630 -1400 2670 -1400 {
lab=C2}
N 2630 -1360 2670 -1360 {
lab=C0}
N 3020 -1480 3060 -1480 {
lab=R6}
N 3020 -1460 3060 -1460 {
lab=R5}
N 3020 -1440 3030 -1440 {
lab=R4}
N 3030 -1440 3060 -1440 {
lab=R4}
N 3020 -1420 3060 -1420 {
lab=R3}
N 3020 -1400 3060 -1400 {
lab=R2}
N 3020 -1380 3060 -1380 {
lab=R1}
N 3020 -1360 3060 -1360 {
lab=R0}
N 2700 -1260 2740 -1260 {
lab=IM_T}
N 2700 -1260 2700 -1230 {
lab=IM_T}
N 2700 -1150 2740 -1150 {
lab=IM}
N 2700 -1150 2700 -1120 {
lab=IM}
N 2740 -1200 2740 -1150 {
lab=IM}
N 2740 -1230 2760 -1230 {
lab=VSS}
N 2760 -1230 2760 -1090 {
lab=VSS}
N 2740 -1090 2760 -1090 {
lab=VSS}
N 2740 -1120 2760 -1120 {
lab=VSS}
N 2630 -1380 2670 -1380 {
lab=C1}
C {MSB_UNIT_CELL.sym} 190 -1680 0 0 {name=x57}
C {MSB_UNIT_CELL.sym} 470 -1680 0 0 {name=x58}
C {MSB_UNIT_CELL.sym} 730 -1680 0 0 {name=x59}
C {MSB_UNIT_CELL.sym} 1010 -1680 0 0 {name=x60}
C {MSB_UNIT_CELL.sym} 1270 -1680 0 0 {name=x61}
C {MSB_UNIT_CELL.sym} 1550 -1680 0 0 {name=x62}
C {MSB_UNIT_CELL.sym} 1810 -1680 0 0 {name=x63}
C {MSB_UNIT_CELL.sym} 2090 -1680 0 0 {name=x64}
C {devices/lab_pin.sym} 210 -1800 0 0 {name=p1 sig_type=std_logic lab=IM}
C {devices/lab_pin.sym} 230 -1790 0 0 {name=p2 sig_type=std_logic lab=IM_T}
C {devices/lab_pin.sym} 250 -1780 0 0 {name=p3 sig_type=std_logic lab=VDD}
C {devices/lab_pin.sym} 330 -1770 0 0 {name=p4 sig_type=std_logic lab=IOUT+}
C {devices/lab_pin.sym} 340 -1760 0 0 {name=p5 sig_type=std_logic lab=IOUT-}
C {devices/lab_pin.sym} 230 -1620 0 0 {name=p6 sig_type=std_logic lab=VSS}
C {MSB_UNIT_CELL.sym} 190 -1460 0 0 {name=x1}
C {MSB_UNIT_CELL.sym} 470 -1460 0 0 {name=x2}
C {MSB_UNIT_CELL.sym} 730 -1460 0 0 {name=x3}
C {MSB_UNIT_CELL.sym} 1010 -1460 0 0 {name=x4}
C {MSB_UNIT_CELL.sym} 1270 -1460 0 0 {name=x5}
C {MSB_UNIT_CELL.sym} 1550 -1460 0 0 {name=x6}
C {MSB_UNIT_CELL.sym} 1810 -1460 0 0 {name=x7}
C {MSB_UNIT_CELL.sym} 2090 -1460 0 0 {name=x8}
C {devices/lab_pin.sym} 210 -1580 0 0 {name=p7 sig_type=std_logic lab=IM}
C {devices/lab_pin.sym} 230 -1570 0 0 {name=p8 sig_type=std_logic lab=IM_T}
C {devices/lab_pin.sym} 250 -1560 0 0 {name=p9 sig_type=std_logic lab=VDD}
C {devices/lab_pin.sym} 330 -1550 0 0 {name=p10 sig_type=std_logic lab=IOUT+}
C {devices/lab_pin.sym} 340 -1540 0 0 {name=p11 sig_type=std_logic lab=IOUT-}
C {devices/lab_pin.sym} 230 -1400 0 0 {name=p12 sig_type=std_logic lab=VSS}
C {MSB_UNIT_CELL.sym} 190 -1240 0 0 {name=x9}
C {MSB_UNIT_CELL.sym} 470 -1240 0 0 {name=x10}
C {MSB_UNIT_CELL.sym} 730 -1240 0 0 {name=x11}
C {MSB_UNIT_CELL.sym} 1010 -1240 0 0 {name=x12}
C {MSB_UNIT_CELL.sym} 1270 -1240 0 0 {name=x13}
C {MSB_UNIT_CELL.sym} 1550 -1240 0 0 {name=x14}
C {MSB_UNIT_CELL.sym} 1810 -1240 0 0 {name=x15}
C {MSB_UNIT_CELL.sym} 2090 -1240 0 0 {name=x16}
C {devices/lab_pin.sym} 210 -1360 0 0 {name=p13 sig_type=std_logic lab=IM}
C {devices/lab_pin.sym} 230 -1350 0 0 {name=p14 sig_type=std_logic lab=IM_T}
C {devices/lab_pin.sym} 250 -1340 0 0 {name=p15 sig_type=std_logic lab=VDD}
C {devices/lab_pin.sym} 330 -1330 0 0 {name=p16 sig_type=std_logic lab=IOUT+}
C {devices/lab_pin.sym} 340 -1320 0 0 {name=p17 sig_type=std_logic lab=IOUT-}
C {devices/lab_pin.sym} 230 -1180 0 0 {name=p18 sig_type=std_logic lab=VSS}
C {MSB_UNIT_CELL.sym} 190 -1020 0 0 {name=x17}
C {MSB_UNIT_CELL.sym} 470 -1020 0 0 {name=x18}
C {MSB_UNIT_CELL.sym} 730 -1020 0 0 {name=x19}
C {MSB_UNIT_CELL.sym} 1010 -1020 0 0 {name=x20}
C {MSB_UNIT_CELL.sym} 1270 -1020 0 0 {name=x21}
C {MSB_UNIT_CELL.sym} 1550 -1020 0 0 {name=x22}
C {MSB_UNIT_CELL.sym} 1810 -1020 0 0 {name=x23}
C {MSB_UNIT_CELL.sym} 2090 -1020 0 0 {name=x24}
C {devices/lab_pin.sym} 210 -1140 0 0 {name=p19 sig_type=std_logic lab=IM}
C {devices/lab_pin.sym} 230 -1130 0 0 {name=p20 sig_type=std_logic lab=IM_T}
C {devices/lab_pin.sym} 250 -1120 0 0 {name=p21 sig_type=std_logic lab=VDD}
C {devices/lab_pin.sym} 330 -1110 0 0 {name=p22 sig_type=std_logic lab=IOUT+}
C {devices/lab_pin.sym} 340 -1100 0 0 {name=p23 sig_type=std_logic lab=IOUT-}
C {devices/lab_pin.sym} 230 -960 0 0 {name=p24 sig_type=std_logic lab=VSS}
C {MSB_UNIT_CELL.sym} 190 -800 0 0 {name=x25}
C {MSB_UNIT_CELL.sym} 470 -800 0 0 {name=x26}
C {MSB_UNIT_CELL.sym} 730 -800 0 0 {name=x27}
C {MSB_UNIT_CELL.sym} 1010 -800 0 0 {name=x28}
C {MSB_UNIT_CELL.sym} 1270 -800 0 0 {name=x29}
C {MSB_UNIT_CELL.sym} 1550 -800 0 0 {name=x30}
C {MSB_UNIT_CELL.sym} 1810 -800 0 0 {name=x31}
C {MSB_UNIT_CELL.sym} 2090 -800 0 0 {name=x32}
C {devices/lab_pin.sym} 210 -920 0 0 {name=p25 sig_type=std_logic lab=IM}
C {devices/lab_pin.sym} 230 -910 0 0 {name=p26 sig_type=std_logic lab=IM_T}
C {devices/lab_pin.sym} 250 -900 0 0 {name=p27 sig_type=std_logic lab=VDD}
C {devices/lab_pin.sym} 330 -890 0 0 {name=p28 sig_type=std_logic lab=IOUT+}
C {devices/lab_pin.sym} 340 -880 0 0 {name=p29 sig_type=std_logic lab=IOUT-}
C {devices/lab_pin.sym} 230 -740 0 0 {name=p30 sig_type=std_logic lab=VSS}
C {MSB_UNIT_CELL.sym} 190 -580 0 0 {name=x33}
C {MSB_UNIT_CELL.sym} 470 -580 0 0 {name=x34}
C {MSB_UNIT_CELL.sym} 730 -580 0 0 {name=x35}
C {MSB_UNIT_CELL.sym} 1010 -580 0 0 {name=x36}
C {MSB_UNIT_CELL.sym} 1270 -580 0 0 {name=x37}
C {MSB_UNIT_CELL.sym} 1550 -580 0 0 {name=x38}
C {MSB_UNIT_CELL.sym} 1810 -580 0 0 {name=x39}
C {MSB_UNIT_CELL.sym} 2090 -580 0 0 {name=x40}
C {devices/lab_pin.sym} 210 -700 0 0 {name=p31 sig_type=std_logic lab=IM}
C {devices/lab_pin.sym} 230 -690 0 0 {name=p32 sig_type=std_logic lab=IM_T}
C {devices/lab_pin.sym} 250 -680 0 0 {name=p33 sig_type=std_logic lab=VDD}
C {devices/lab_pin.sym} 330 -670 0 0 {name=p34 sig_type=std_logic lab=IOUT+}
C {devices/lab_pin.sym} 340 -660 0 0 {name=p35 sig_type=std_logic lab=IOUT-}
C {devices/lab_pin.sym} 230 -520 0 0 {name=p36 sig_type=std_logic lab=VSS}
C {MSB_UNIT_CELL.sym} 190 -360 0 0 {name=x41}
C {MSB_UNIT_CELL.sym} 470 -360 0 0 {name=x42}
C {MSB_UNIT_CELL.sym} 730 -360 0 0 {name=x43}
C {MSB_UNIT_CELL.sym} 1010 -360 0 0 {name=x44}
C {MSB_UNIT_CELL.sym} 1270 -360 0 0 {name=x45}
C {MSB_UNIT_CELL.sym} 1550 -360 0 0 {name=x46}
C {MSB_UNIT_CELL.sym} 1810 -360 0 0 {name=x47}
C {MSB_UNIT_CELL.sym} 2090 -360 0 0 {name=x48}
C {devices/lab_pin.sym} 210 -480 0 0 {name=p37 sig_type=std_logic lab=IM}
C {devices/lab_pin.sym} 230 -470 0 0 {name=p38 sig_type=std_logic lab=IM_T}
C {devices/lab_pin.sym} 250 -460 0 0 {name=p39 sig_type=std_logic lab=VDD}
C {devices/lab_pin.sym} 330 -450 0 0 {name=p40 sig_type=std_logic lab=IOUT+}
C {devices/lab_pin.sym} 340 -440 0 0 {name=p41 sig_type=std_logic lab=IOUT-}
C {devices/lab_pin.sym} 230 -300 0 0 {name=p42 sig_type=std_logic lab=VSS}
C {MSB_UNIT_CELL.sym} 190 -140 0 0 {name=x49}
C {MSB_UNIT_CELL.sym} 470 -140 0 0 {name=x50}
C {MSB_UNIT_CELL.sym} 730 -140 0 0 {name=x51}
C {MSB_UNIT_CELL.sym} 1010 -140 0 0 {name=x52}
C {MSB_UNIT_CELL.sym} 1270 -140 0 0 {name=x53}
C {MSB_UNIT_CELL.sym} 1550 -140 0 0 {name=x54}
C {MSB_UNIT_CELL.sym} 1810 -140 0 0 {name=x55}
C {devices/lab_pin.sym} 210 -260 0 0 {name=p43 sig_type=std_logic lab=IM}
C {devices/lab_pin.sym} 230 -250 0 0 {name=p44 sig_type=std_logic lab=IM_T}
C {devices/lab_pin.sym} 250 -240 0 0 {name=p45 sig_type=std_logic lab=VDD}
C {devices/lab_pin.sym} 330 -230 0 0 {name=p46 sig_type=std_logic lab=IOUT+}
C {devices/lab_pin.sym} 340 -220 0 0 {name=p47 sig_type=std_logic lab=IOUT-}
C {devices/lab_pin.sym} 230 -80 0 0 {name=p48 sig_type=std_logic lab=VSS}
C {devices/lab_pin.sym} 110 -1710 0 0 {name=p49 sig_type=std_logic lab=VDD}
C {devices/lab_pin.sym} 120 -1690 0 0 {name=p50 sig_type=std_logic lab=R0}
C {devices/lab_pin.sym} 130 -1670 0 0 {name=p51 sig_type=std_logic lab=C0}
C {devices/lab_pin.sym} 110 -1490 0 0 {name=p52 sig_type=std_logic lab=R0}
C {devices/lab_pin.sym} 400 -1670 0 0 {name=p53 sig_type=std_logic lab=C1}
C {devices/lab_pin.sym} 660 -1670 0 0 {name=p54 sig_type=std_logic lab=C2}
C {devices/lab_pin.sym} 930 -1670 0 0 {name=p55 sig_type=std_logic lab=C3}
C {devices/lab_pin.sym} 1200 -1670 0 0 {name=p56 sig_type=std_logic lab=C4}
C {devices/lab_pin.sym} 1470 -1670 0 0 {name=p57 sig_type=std_logic lab=C5}
C {devices/lab_pin.sym} 1740 -1670 0 0 {name=p58 sig_type=std_logic lab=C6}
C {devices/lab_pin.sym} 2020 -1670 0 0 {name=p59 sig_type=std_logic lab=VSS}
C {devices/lab_pin.sym} 120 -1470 0 0 {name=p60 sig_type=std_logic lab=R1}
C {devices/lab_pin.sym} 110 -1270 0 0 {name=p61 sig_type=std_logic lab=R1}
C {devices/lab_pin.sym} 120 -1250 0 0 {name=p62 sig_type=std_logic lab=R2}
C {devices/lab_pin.sym} 110 -1050 0 0 {name=p63 sig_type=std_logic lab=R2}
C {devices/lab_pin.sym} 120 -1030 0 0 {name=p64 sig_type=std_logic lab=R3}
C {devices/lab_pin.sym} 110 -830 0 0 {name=p65 sig_type=std_logic lab=R3}
C {devices/lab_pin.sym} 120 -810 0 0 {name=p66 sig_type=std_logic lab=R4}
C {devices/lab_pin.sym} 110 -610 0 0 {name=p67 sig_type=std_logic lab=R4}
C {devices/lab_pin.sym} 120 -590 0 0 {name=p68 sig_type=std_logic lab=R5}
C {devices/lab_pin.sym} 110 -390 0 0 {name=p69 sig_type=std_logic lab=R5}
C {devices/lab_pin.sym} 120 -370 0 0 {name=p70 sig_type=std_logic lab=R6}
C {devices/lab_pin.sym} 110 -170 0 0 {name=p71 sig_type=std_logic lab=R6}
C {devices/lab_pin.sym} 120 -150 0 0 {name=p72 sig_type=std_logic lab=VSS}
C {Thermo_Decoder.sym} 2490 -1400 0 0 {name=x56}
C {Thermo_Decoder.sym} 2880 -1400 0 0 {name=x65}
C {devices/lab_pin.sym} 2680 -1510 0 0 {name=p73 sig_type=std_logic lab=VDD}
C {devices/lab_pin.sym} 2700 -1330 0 0 {name=p74 sig_type=std_logic lab=VSS}
C {devices/lab_pin.sym} 2670 -1480 0 0 {name=p76 sig_type=std_logic lab=C6}
C {devices/lab_pin.sym} 2670 -1460 0 0 {name=p78 sig_type=std_logic lab=C5}
C {devices/lab_pin.sym} 2670 -1440 0 0 {name=p80 sig_type=std_logic lab=C4}
C {devices/lab_pin.sym} 2670 -1420 0 0 {name=p82 sig_type=std_logic lab=C3}
C {devices/lab_pin.sym} 2670 -1400 0 0 {name=p84 sig_type=std_logic lab=C2}
C {devices/lab_pin.sym} 2670 -1380 0 0 {name=p86 sig_type=std_logic lab=C1}
C {devices/lab_pin.sym} 2670 -1360 0 0 {name=p88 sig_type=std_logic lab=C0}
C {devices/lab_pin.sym} 3060 -1480 0 0 {name=p79 sig_type=std_logic lab=R6}
C {devices/lab_pin.sym} 3060 -1460 0 0 {name=p81 sig_type=std_logic lab=R5}
C {devices/lab_pin.sym} 3060 -1440 0 0 {name=p83 sig_type=std_logic lab=R4}
C {devices/lab_pin.sym} 3060 -1420 0 0 {name=p85 sig_type=std_logic lab=R3}
C {devices/lab_pin.sym} 3060 -1400 0 0 {name=p87 sig_type=std_logic lab=R2}
C {devices/lab_pin.sym} 3060 -1380 0 0 {name=p89 sig_type=std_logic lab=R1}
C {devices/lab_pin.sym} 3060 -1360 0 0 {name=p90 sig_type=std_logic lab=R0}
C {devices/lab_pin.sym} 2360 -1440 0 0 {name=p91 sig_type=std_logic lab=B9}
C {devices/lab_pin.sym} 2360 -1420 0 0 {name=p92 sig_type=std_logic lab=B8}
C {devices/lab_pin.sym} 2360 -1400 0 0 {name=p93 sig_type=std_logic lab=B7}
C {devices/lab_pin.sym} 2750 -1440 0 0 {name=p94 sig_type=std_logic lab=B12}
C {devices/lab_pin.sym} 2750 -1420 0 0 {name=p95 sig_type=std_logic lab=B11}
C {devices/lab_pin.sym} 2750 -1400 0 0 {name=p96 sig_type=std_logic lab=B10}
C {devices/iopin.sym} 2370 -1260 0 0 {name=p97 lab=VDD}
C {devices/iopin.sym} 2460 -1260 0 0 {name=p98 lab=VSS}
C {devices/ipin.sym} 2420 -1220 0 0 {name=p99 lab=B7}
C {devices/ipin.sym} 2510 -1220 0 0 {name=p100 lab=B11}
C {devices/ipin.sym} 2420 -1190 0 0 {name=p101 lab=B8}
C {devices/ipin.sym} 2510 -1190 0 0 {name=p102 lab=B12}
C {devices/ipin.sym} 2420 -1160 0 0 {name=p103 lab=B9}
C {devices/ipin.sym} 2510 -1160 0 0 {name=p104 lab=IM_T}
C {devices/ipin.sym} 2420 -1130 0 0 {name=p105 lab=B10}
C {devices/opin.sym} 2370 -1090 0 0 {name=p106 lab=IOUT+}
C {devices/opin.sym} 2460 -1090 0 0 {name=p107 lab=IOUT-}
C {symbols/nfet_03v3.sym} 2720 -1230 0 0 {name=M1
L=0.5u
W=0.6u
nf=1
m=1
ad="'int((nf+1)/2) * W/nf * 0.18u'"
pd="'2*int((nf+1)/2) * (W/nf + 0.18u)'"
as="'int((nf+2)/2) * W/nf * 0.18u'"
ps="'2*int((nf+2)/2) * (W/nf + 0.18u)'"
nrd="'0.18u / W'" nrs="'0.18u / W'"
sa=0 sb=0 sd=0
model=nfet_03v3
spiceprefix=X
}
C {symbols/nfet_03v3.sym} 2720 -1120 0 0 {name=M2
L=0.5u
W=0.6u
nf=1
m=1
ad="'int((nf+1)/2) * W/nf * 0.18u'"
pd="'2*int((nf+1)/2) * (W/nf + 0.18u)'"
as="'int((nf+2)/2) * W/nf * 0.18u'"
ps="'2*int((nf+2)/2) * (W/nf + 0.18u)'"
nrd="'0.18u / W'" nrs="'0.18u / W'"
sa=0 sb=0 sd=0
model=nfet_03v3
spiceprefix=X
}
C {devices/lab_pin.sym} 2760 -1180 0 0 {name=p108 sig_type=std_logic lab=VSS
L=0.5u
W=0.6u}
C {devices/lab_pin.sym} 2700 -1260 0 0 {name=p109 sig_type=std_logic lab=IM_T
L=0.5u
W=0.6u}
C {devices/lab_pin.sym} 2700 -1150 0 0 {name=p110 sig_type=std_logic lab=IM
L=0.5u
W=0.6u}
